VERSION 5.7 ;
  NOWIREEXTENSIONATPIN ON ;
  DIVIDERCHAR "/" ;
  BUSBITCHARS "[]" ;
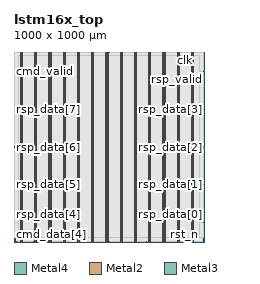
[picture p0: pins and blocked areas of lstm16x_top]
MACRO lstm16x_top
  CLASS BLOCK ;
  FOREIGN lstm16x_top ;
  ORIGIN 0.000 0.000 ;
  SIZE 1000.000 BY 1000.000 ;
  PIN VDD
    DIRECTION INOUT ;
    USE POWER ;
    PORT
      LAYER Metal4 ;
        RECT 33.980 0.000 38.980 1000.000 ;
    END
    PORT
      LAYER Metal4 ;
        RECT 108.980 0.000 113.980 1000.000 ;
    END
    PORT
      LAYER Metal4 ;
        RECT 183.980 0.000 188.980 1000.000 ;
    END
    PORT
      LAYER Metal4 ;
        RECT 258.980 0.000 263.980 1000.000 ;
    END
    PORT
      LAYER Metal4 ;
        RECT 333.980 0.000 338.980 1000.000 ;
    END
    PORT
      LAYER Metal4 ;
        RECT 408.980 0.000 413.980 1000.000 ;
    END
    PORT
      LAYER Metal4 ;
        RECT 483.980 0.000 488.980 1000.000 ;
    END
    PORT
      LAYER Metal4 ;
        RECT 558.980 0.000 563.980 1000.000 ;
    END
    PORT
      LAYER Metal4 ;
        RECT 633.980 0.000 638.980 1000.000 ;
    END
    PORT
      LAYER Metal4 ;
        RECT 708.980 0.000 713.980 1000.000 ;
    END
    PORT
      LAYER Metal4 ;
        RECT 783.980 0.000 788.980 1000.000 ;
    END
    PORT
      LAYER Metal4 ;
        RECT 858.980 0.000 863.980 1000.000 ;
    END
    PORT
      LAYER Metal4 ;
        RECT 933.980 0.000 938.980 1000.000 ;
    END
  END VDD
  PIN VSS
    DIRECTION INOUT ;
    USE GROUND ;
    PORT
      LAYER Metal4 ;
        RECT 39.980 0.000 44.980 1000.000 ;
    END
    PORT
      LAYER Metal4 ;
        RECT 114.980 0.000 119.980 1000.000 ;
    END
    PORT
      LAYER Metal4 ;
        RECT 189.980 0.000 194.980 1000.000 ;
    END
    PORT
      LAYER Metal4 ;
        RECT 264.980 0.000 269.980 1000.000 ;
    END
    PORT
      LAYER Metal4 ;
        RECT 339.980 0.000 344.980 1000.000 ;
    END
    PORT
      LAYER Metal4 ;
        RECT 414.980 0.000 419.980 1000.000 ;
    END
    PORT
      LAYER Metal4 ;
        RECT 489.980 0.000 494.980 1000.000 ;
    END
    PORT
      LAYER Metal4 ;
        RECT 564.980 0.000 569.980 1000.000 ;
    END
    PORT
      LAYER Metal4 ;
        RECT 639.980 0.000 644.980 1000.000 ;
    END
    PORT
      LAYER Metal4 ;
        RECT 714.980 0.000 719.980 1000.000 ;
    END
    PORT
      LAYER Metal4 ;
        RECT 789.980 0.000 794.980 1000.000 ;
    END
    PORT
      LAYER Metal4 ;
        RECT 864.980 0.000 869.980 1000.000 ;
    END
    PORT
      LAYER Metal4 ;
        RECT 939.980 0.000 944.980 1000.000 ;
    END
  END VSS
  PIN clk
    DIRECTION INPUT ;
    USE SIGNAL ;
    ANTENNAGATEAREA 4.738000 ;
    ANTENNADIFFAREA 0.410400 ;
    PORT
      LAYER Metal2 ;
        RECT 898.240 999.440 898.800 1000.000 ;
    END
  END clk
  PIN cmd_data[0]
    DIRECTION INPUT ;
    USE SIGNAL ;
    ANTENNAGATEAREA 0.498500 ;
    ANTENNADIFFAREA 0.410400 ;
    PORT
      LAYER Metal2 ;
        RECT 100.800 999.440 101.360 1000.000 ;
    END
  END cmd_data[0]
  PIN cmd_data[1]
    DIRECTION INPUT ;
    USE SIGNAL ;
    ANTENNAGATEAREA 1.102000 ;
    ANTENNADIFFAREA 0.410400 ;
    PORT
      LAYER Metal2 ;
        RECT 300.160 999.440 300.720 1000.000 ;
    END
  END cmd_data[1]
  PIN cmd_data[2]
    DIRECTION INPUT ;
    USE SIGNAL ;
    ANTENNAGATEAREA 0.396000 ;
    ANTENNADIFFAREA 0.410400 ;
    PORT
      LAYER Metal2 ;
        RECT 499.520 999.440 500.080 1000.000 ;
    END
  END cmd_data[2]
  PIN cmd_data[3]
    DIRECTION INPUT ;
    USE SIGNAL ;
    ANTENNAGATEAREA 0.396000 ;
    ANTENNADIFFAREA 0.410400 ;
    PORT
      LAYER Metal2 ;
        RECT 698.880 999.440 699.440 1000.000 ;
    END
  END cmd_data[3]
  PIN cmd_data[4]
    DIRECTION INPUT ;
    USE SIGNAL ;
    ANTENNAGATEAREA 0.396000 ;
    ANTENNADIFFAREA 0.410400 ;
    PORT
      LAYER Metal2 ;
        RECT 100.800 0.000 101.360 0.560 ;
    END
  END cmd_data[4]
  PIN cmd_data[5]
    DIRECTION INPUT ;
    USE SIGNAL ;
    ANTENNAGATEAREA 0.396000 ;
    ANTENNADIFFAREA 0.410400 ;
    PORT
      LAYER Metal2 ;
        RECT 300.160 0.000 300.720 0.560 ;
    END
  END cmd_data[5]
  PIN cmd_data[6]
    DIRECTION INPUT ;
    USE SIGNAL ;
    ANTENNAGATEAREA 0.396000 ;
    ANTENNADIFFAREA 0.410400 ;
    PORT
      LAYER Metal2 ;
        RECT 499.520 0.000 500.080 0.560 ;
    END
  END cmd_data[6]
  PIN cmd_data[7]
    DIRECTION INPUT ;
    USE SIGNAL ;
    ANTENNAGATEAREA 0.396000 ;
    ANTENNADIFFAREA 0.410400 ;
    PORT
      LAYER Metal2 ;
        RECT 698.880 0.000 699.440 0.560 ;
    END
  END cmd_data[7]
  PIN cmd_valid
    DIRECTION INPUT ;
    USE SIGNAL ;
    ANTENNAGATEAREA 0.396000 ;
    ANTENNADIFFAREA 0.410400 ;
    PORT
      LAYER Metal3 ;
        RECT 0.000 898.240 0.560 898.800 ;
    END
  END cmd_valid
  PIN rsp_data[0]
    DIRECTION OUTPUT ;
    USE SIGNAL ;
    ANTENNADIFFAREA 0.897600 ;
    PORT
      LAYER Metal3 ;
        RECT 999.440 100.800 1000.000 101.360 ;
    END
  END rsp_data[0]
  PIN rsp_data[1]
    DIRECTION OUTPUT ;
    USE SIGNAL ;
    ANTENNADIFFAREA 0.897600 ;
    PORT
      LAYER Metal3 ;
        RECT 999.440 300.160 1000.000 300.720 ;
    END
  END rsp_data[1]
  PIN rsp_data[2]
    DIRECTION OUTPUT ;
    USE SIGNAL ;
    ANTENNADIFFAREA 0.897600 ;
    PORT
      LAYER Metal3 ;
        RECT 999.440 499.520 1000.000 500.080 ;
    END
  END rsp_data[2]
  PIN rsp_data[3]
    DIRECTION OUTPUT ;
    USE SIGNAL ;
    ANTENNADIFFAREA 0.897600 ;
    PORT
      LAYER Metal3 ;
        RECT 999.440 698.880 1000.000 699.440 ;
    END
  END rsp_data[3]
  PIN rsp_data[4]
    DIRECTION OUTPUT ;
    USE SIGNAL ;
    ANTENNADIFFAREA 0.897600 ;
    PORT
      LAYER Metal3 ;
        RECT 0.000 100.800 0.560 101.360 ;
    END
  END rsp_data[4]
  PIN rsp_data[5]
    DIRECTION OUTPUT ;
    USE SIGNAL ;
    ANTENNADIFFAREA 0.897600 ;
    PORT
      LAYER Metal3 ;
        RECT 0.000 300.160 0.560 300.720 ;
    END
  END rsp_data[5]
  PIN rsp_data[6]
    DIRECTION OUTPUT ;
    USE SIGNAL ;
    ANTENNADIFFAREA 0.897600 ;
    PORT
      LAYER Metal3 ;
        RECT 0.000 499.520 0.560 500.080 ;
    END
  END rsp_data[6]
  PIN rsp_data[7]
    DIRECTION OUTPUT ;
    USE SIGNAL ;
    ANTENNADIFFAREA 0.897600 ;
    PORT
      LAYER Metal3 ;
        RECT 0.000 698.880 0.560 699.440 ;
    END
  END rsp_data[7]
  PIN rsp_valid
    DIRECTION OUTPUT ;
    USE SIGNAL ;
    ANTENNADIFFAREA 0.897600 ;
    PORT
      LAYER Metal3 ;
        RECT 999.440 898.240 1000.000 898.800 ;
    END
  END rsp_valid
  PIN rst_n
    DIRECTION INPUT ;
    USE SIGNAL ;
    ANTENNAGATEAREA 6.612000 ;
    ANTENNADIFFAREA 0.410400 ;
    PORT
      LAYER Metal2 ;
        RECT 898.240 0.000 898.800 0.560 ;
    END
  END rst_n
  OBS
      LAYER Nwell ;
        RECT 19.730 23.090 980.430 980.430 ;
      LAYER Metal1 ;
        RECT 20.160 23.220 980.000 980.300 ;
      LAYER Metal2 ;
        RECT 20.300 999.140 100.500 999.860 ;
        RECT 101.660 999.140 299.860 999.860 ;
        RECT 301.020 999.140 499.220 999.860 ;
        RECT 500.380 999.140 698.580 999.860 ;
        RECT 699.740 999.140 897.940 999.860 ;
        RECT 899.100 999.140 991.620 999.860 ;
        RECT 20.300 0.860 991.620 999.140 ;
        RECT 20.300 0.560 100.500 0.860 ;
        RECT 101.660 0.560 299.860 0.860 ;
        RECT 301.020 0.560 499.220 0.860 ;
        RECT 500.380 0.560 698.580 0.860 ;
        RECT 699.740 0.560 897.940 0.860 ;
        RECT 899.100 0.560 991.620 0.860 ;
      LAYER Metal3 ;
        RECT 0.560 899.100 999.440 999.460 ;
        RECT 0.860 897.940 999.140 899.100 ;
        RECT 0.560 699.740 999.440 897.940 ;
        RECT 0.860 698.580 999.140 699.740 ;
        RECT 0.560 500.380 999.440 698.580 ;
        RECT 0.860 499.220 999.140 500.380 ;
        RECT 0.560 301.020 999.440 499.220 ;
        RECT 0.860 299.860 999.140 301.020 ;
        RECT 0.560 101.660 999.440 299.860 ;
        RECT 0.860 100.500 999.140 101.660 ;
        RECT 0.560 21.980 999.440 100.500 ;
      LAYER Metal4 ;
        RECT 23.660 24.730 33.680 979.350 ;
        RECT 39.280 24.730 39.680 979.350 ;
        RECT 45.280 24.730 108.680 979.350 ;
        RECT 114.280 24.730 114.680 979.350 ;
        RECT 120.280 24.730 183.680 979.350 ;
        RECT 189.280 24.730 189.680 979.350 ;
        RECT 195.280 24.730 258.680 979.350 ;
        RECT 264.280 24.730 264.680 979.350 ;
        RECT 270.280 24.730 333.680 979.350 ;
        RECT 339.280 24.730 339.680 979.350 ;
        RECT 345.280 24.730 408.680 979.350 ;
        RECT 414.280 24.730 414.680 979.350 ;
        RECT 420.280 24.730 483.680 979.350 ;
        RECT 489.280 24.730 489.680 979.350 ;
        RECT 495.280 24.730 558.680 979.350 ;
        RECT 564.280 24.730 564.680 979.350 ;
        RECT 570.280 24.730 633.680 979.350 ;
        RECT 639.280 24.730 639.680 979.350 ;
        RECT 645.280 24.730 708.680 979.350 ;
        RECT 714.280 24.730 714.680 979.350 ;
        RECT 720.280 24.730 783.680 979.350 ;
        RECT 789.280 24.730 789.680 979.350 ;
        RECT 795.280 24.730 858.680 979.350 ;
        RECT 864.280 24.730 864.680 979.350 ;
        RECT 870.280 24.730 933.680 979.350 ;
        RECT 939.280 24.730 939.680 979.350 ;
        RECT 945.280 24.730 975.940 979.350 ;
  END
END lstm16x_top
END LIBRARY

